VERSION 5.7 ;
  NOWIREEXTENSIONATPIN ON ;
  DIVIDERCHAR "/" ;
  BUSBITCHARS "[]" ;
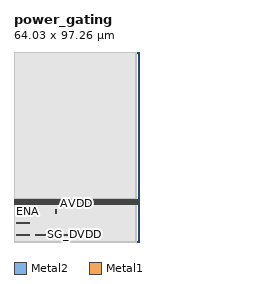
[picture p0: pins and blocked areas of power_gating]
MACRO power_gating
  CLASS BLOCK ;
  FOREIGN power_gating ;
  ORIGIN 0.030 0.000 ;
  SIZE 64.030 BY 97.260 ;
  PIN DOUT
    ANTENNADIFFAREA 5.274400 ;
    PORT
      LAYER Metal2 ;
        RECT 37.025 3.195 41.315 3.785 ;
    END
  END DOUT
  PIN SG_AVDD
    ANTENNADIFFAREA 10.335999 ;
    PORT
      LAYER Metal2 ;
        RECT 20.275 3.195 27.125 3.785 ;
    END
  END SG_AVDD
  PIN DVDD
    ANTENNADIFFAREA 23.500599 ;
    PORT
      LAYER Metal1 ;
        RECT 0.000 20.440 64.000 20.940 ;
    END
  END DVDD
  PIN EG_IBIAS
    ANTENNADIFFAREA 5.824000 ;
    PORT
      LAYER Metal2 ;
        RECT 1.435 9.315 7.885 9.905 ;
    END
  END EG_IBIAS
  PIN SG_DVDD
    ANTENNADIFFAREA 10.548800 ;
    PORT
      LAYER Metal2 ;
        RECT 30.285 3.195 31.465 3.785 ;
    END
  END SG_DVDD
  PIN AVDD
    ANTENNADIFFAREA 63.647999 ;
    PORT
      LAYER Metal1 ;
        RECT 0.000 19.440 64.000 19.940 ;
    END
  END AVDD
  PIN IBIAS
    ANTENNADIFFAREA 9.728000 ;
    PORT
      LAYER Metal2 ;
        RECT 1.435 3.195 7.885 3.785 ;
    END
  END IBIAS
  PIN EG_AVDD
    ANTENNADIFFAREA 10.335999 ;
    PORT
      LAYER Metal2 ;
        RECT 10.755 3.195 16.265 3.785 ;
    END
  END EG_AVDD
  PIN ENA
    ANTENNAGATEAREA 0.226200 ;
    PORT
      LAYER Metal2 ;
        RECT 1.335 14.655 1.635 16.715 ;
    END
  END ENA
  PIN STDBY
    ANTENNAGATEAREA 11.052600 ;
    PORT
      LAYER Metal2 ;
        RECT 21.335 14.655 21.635 16.715 ;
    END
  END STDBY
  PIN VSS
    USE GROUND ;
    PORT
      LAYER Metal1 ;
        RECT 0.000 21.440 64.000 21.940 ;
    END
  END VSS
  OBS
      LAYER GatPoly ;
        RECT 0.310 0.420 42.130 18.645 ;
      LAYER Metal1 ;
        RECT -0.030 22.120 62.790 97.260 ;
        RECT -0.030 21.120 62.790 21.260 ;
        RECT -0.030 20.120 62.790 20.260 ;
        RECT -0.030 0.000 62.790 19.260 ;
      LAYER Metal2 ;
        RECT 0.000 16.925 62.830 97.260 ;
        RECT 0.000 14.445 1.125 16.925 ;
        RECT 1.845 14.445 21.125 16.925 ;
        RECT 21.845 14.445 62.830 16.925 ;
        RECT 0.000 10.115 62.830 14.445 ;
        RECT 0.000 9.105 1.225 10.115 ;
        RECT 8.095 9.105 62.830 10.115 ;
        RECT 0.000 3.995 62.830 9.105 ;
        RECT 0.000 2.985 1.225 3.995 ;
        RECT 8.095 2.985 10.545 3.995 ;
        RECT 16.475 2.985 20.065 3.995 ;
        RECT 27.335 2.985 30.075 3.995 ;
        RECT 31.675 2.985 36.815 3.995 ;
        RECT 41.525 2.985 62.830 3.995 ;
        RECT 0.000 0.000 62.830 2.985 ;
      LAYER Metal3 ;
        RECT 0.000 0.045 62.000 97.260 ;
      LAYER Metal4 ;
        RECT 0.000 22.260 62.000 97.260 ;
  END
END power_gating
END LIBRARY

